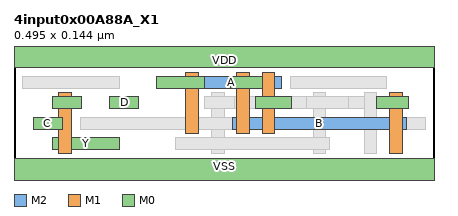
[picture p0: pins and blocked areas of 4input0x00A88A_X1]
MACRO 4input0x00A88A_X1
  CLASS CORE ;
  ORIGIN 0 0 ;
  FOREIGN 4input0x00A88A_X1 0 0 ;
  SIZE 0.4950 BY 0.1440 ;
  SYMMETRY X Y ;
  SITE coresite ;
  PIN A
    DIRECTION INPUT ;
    USE SIGNAL ;
    PORT
      LAYER M2 ;
        RECT 0.1980 0.1010 0.3150 0.1150 ;
      LAYER M1 ;
        RECT 0.2025 0.0480 0.2175 0.1200 ;
        RECT 0.2925 0.0480 0.3075 0.1200 ;
      LAYER M0 ;
        RECT 0.2850 0.0770 0.3270 0.0910 ;
        RECT 0.1680 0.1010 0.2250 0.1150 ;
    END
  END A
  PIN B
    DIRECTION INPUT ;
    USE SIGNAL ;
    PORT
      LAYER M2 ;
        RECT 0.2580 0.0530 0.4620 0.0670 ;
      LAYER M1 ;
        RECT 0.2625 0.0480 0.2775 0.1200 ;
        RECT 0.4425 0.0240 0.4575 0.0960 ;
      LAYER M0 ;
        RECT 0.4275 0.0770 0.4650 0.0910 ;
        RECT 0.2550 0.1010 0.2925 0.1150 ;
    END
  END B
  PIN C
    DIRECTION INPUT ;
    USE SIGNAL ;
    PORT
      LAYER M0 ;
        RECT 0.0225 0.0530 0.0570 0.0670 ;
    END
  END C
  PIN D
    DIRECTION INPUT ;
    USE SIGNAL ;
    PORT
      LAYER M0 ;
        RECT 0.1125 0.0770 0.1470 0.0910 ;
    END
  END D
  PIN Y
    DIRECTION OUTPUT ;
    USE SIGNAL ;
    PORT
      LAYER M1 ;
        RECT 0.0525 0.0240 0.0675 0.0960 ;
      LAYER M0 ;
        RECT 0.0450 0.0770 0.0795 0.0910 ;
        RECT 0.0450 0.0290 0.1245 0.0430 ;
    END
  END Y
  PIN VDD
    DIRECTION INOUT ;
    USE POWER ;
    SHAPE ABUTMENT ;
    PORT
      LAYER M0 ;
        RECT 0.0000 0.1260 0.4950 0.1620 ;
    END
  END VDD
  PIN VSS
    DIRECTION INOUT ;
    USE GROUND ;
    SHAPE ABUTMENT ;
    PORT
      LAYER M0 ;
        RECT 0.0000 -0.0180 0.4950 0.0180 ;
    END
  END VSS
  OBS
    LAYER M2 ;
      RECT 0.2250 0.0770 0.4320 0.0910 ;
    LAYER V1 ;
      RECT 0.2030 0.1010 0.2170 0.1150 ;
      RECT 0.2930 0.1010 0.3070 0.1150 ;
      RECT 0.2330 0.0770 0.2470 0.0910 ;
      RECT 0.4130 0.0770 0.4270 0.0910 ;
      RECT 0.2630 0.0530 0.2770 0.0670 ;
      RECT 0.4430 0.0530 0.4570 0.0670 ;
    LAYER M1 ;
      RECT 0.2325 0.0240 0.2475 0.0960 ;
      RECT 0.3525 0.0240 0.3675 0.0960 ;
      RECT 0.4125 0.0240 0.4275 0.0960 ;
    LAYER V0 ;
      RECT 0.2030 0.1010 0.2170 0.1150 ;
      RECT 0.2930 0.0770 0.3070 0.0910 ;
      RECT 0.0530 0.0770 0.0670 0.0910 ;
      RECT 0.0530 0.0290 0.0670 0.0430 ;
      RECT 0.2330 0.0770 0.2470 0.0910 ;
      RECT 0.4130 0.0530 0.4270 0.0670 ;
      RECT 0.3530 0.0770 0.3670 0.0910 ;
      RECT 0.3530 0.0530 0.3670 0.0670 ;
      RECT 0.2630 0.1010 0.2770 0.1150 ;
      RECT 0.4430 0.0770 0.4570 0.0910 ;
    LAYER M0 ;
      RECT 0.1905 0.0290 0.3720 0.0430 ;
      RECT 0.0780 0.0530 0.3750 0.0670 ;
      RECT 0.3930 0.0530 0.4845 0.0670 ;
      RECT 0.2250 0.0770 0.2595 0.0910 ;
      RECT 0.3450 0.0770 0.3945 0.0910 ;
      RECT 0.0105 0.1010 0.1245 0.1150 ;
      RECT 0.3255 0.1010 0.4395 0.1150 ;
  END
END 4input0x00A88A_X1
